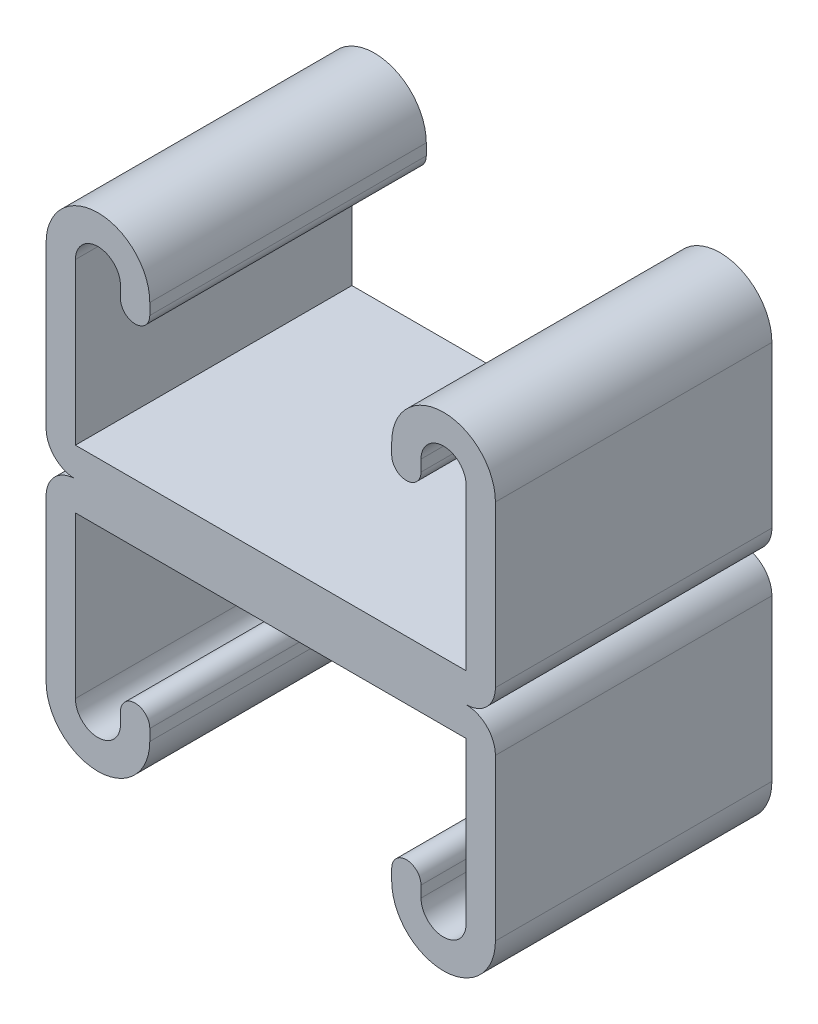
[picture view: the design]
ISO-10303-21;
HEADER;
FILE_DESCRIPTION(('STEP AP214'),'2;1');
FILE_NAME('part.step','',(''),(''),'','','');
FILE_SCHEMA(('AUTOMOTIVE_DESIGN { 1 0 10303 214 1 1 1 1 }'));
ENDSEC;
DATA;
#1=APPLICATION_CONTEXT('core data for automotive mechanical design processes');
#2=APPLICATION_PROTOCOL_DEFINITION('international standard','automotive_design',2000,#1);
#3=PRODUCT_CONTEXT('',#1,'mechanical');
#4=PRODUCT('Part','Part','',(#3));
#5=PRODUCT_RELATED_PRODUCT_CATEGORY('part','',(#4));
#6=PRODUCT_DEFINITION_FORMATION('','',#4);
#7=PRODUCT_DEFINITION_CONTEXT('part definition',#1,'design');
#8=PRODUCT_DEFINITION('design','',#6,#7);
#9=PRODUCT_DEFINITION_SHAPE('','',#8);
#10=(LENGTH_UNIT() NAMED_UNIT(*) SI_UNIT(.MILLI.,.METRE.));
#11=(NAMED_UNIT(*) PLANE_ANGLE_UNIT() SI_UNIT($,.RADIAN.));
#12=(NAMED_UNIT(*) SI_UNIT($,.STERADIAN.) SOLID_ANGLE_UNIT());
#13=UNCERTAINTY_MEASURE_WITH_UNIT(LENGTH_MEASURE(1.E-05),#10,'distance_accuracy_value','');
#14=(GEOMETRIC_REPRESENTATION_CONTEXT(3) GLOBAL_UNCERTAINTY_ASSIGNED_CONTEXT((#13)) GLOBAL_UNIT_ASSIGNED_CONTEXT((#10,
#11,#12)) REPRESENTATION_CONTEXT('',''));
#15=CARTESIAN_POINT('',(0.,0.,0.));
#16=DIRECTION('',(0.,0.,1.));
#17=DIRECTION('',(1.,0.,0.));
#18=AXIS2_PLACEMENT_3D('',#15,#16,#17);
#19=CARTESIAN_POINT('',(-15.875,17.4625,12.7));
#20=DIRECTION('',(0.,0.,-1.));
#21=DIRECTION('',(-1.,0.,0.));
#22=AXIS2_PLACEMENT_3D('',#19,#20,#21);
#23=CYLINDRICAL_SURFACE('',#22,4.7625);
#24=CARTESIAN_POINT('',(-15.875,17.4625,-12.7));
#25=DIRECTION('',(0.,0.,1.));
#26=DIRECTION('',(-1.,0.,0.));
#27=AXIS2_PLACEMENT_3D('',#24,#25,#26);
#28=CIRCLE('',#27,4.7625);
#29=CARTESIAN_POINT('',(-11.1125,17.4625,-12.7));
#30=VERTEX_POINT('',#29);
#31=CARTESIAN_POINT('',(-20.6375,17.4625,-12.7));
#32=VERTEX_POINT('',#31);
#33=EDGE_CURVE('E196',#30,#32,#28,.T.);
#34=ORIENTED_EDGE('',*,*,#33,.T.);
#35=DIRECTION('',(0.,0.,-1.));
#36=VECTOR('',#35,1.);
#37=CARTESIAN_POINT('',(-20.6375,17.4625,12.7));
#38=LINE('',#37,#36);
#39=CARTESIAN_POINT('',(-20.6375,17.4625,12.7));
#40=VERTEX_POINT('',#39);
#41=EDGE_CURVE('E11',#40,#32,#38,.T.);
#42=ORIENTED_EDGE('',*,*,#41,.F.);
#43=CARTESIAN_POINT('',(-15.875,17.4625,12.7));
#44=DIRECTION('',(0.,0.,1.));
#45=DIRECTION('',(-1.,0.,0.));
#46=AXIS2_PLACEMENT_3D('',#43,#44,#45);
#47=CIRCLE('',#46,4.7625);
#48=CARTESIAN_POINT('',(-11.1125,17.4625,12.7));
#49=VERTEX_POINT('',#48);
#50=EDGE_CURVE('E229',#49,#40,#47,.T.);
#51=ORIENTED_EDGE('',*,*,#50,.F.);
#52=DIRECTION('',(0.,0.,-1.));
#53=VECTOR('',#52,1.);
#54=CARTESIAN_POINT('',(-11.1125,17.4625,12.7));
#55=LINE('',#54,#53);
#56=EDGE_CURVE('E192',#49,#30,#55,.T.);
#57=ORIENTED_EDGE('',*,*,#56,.T.);
#58=EDGE_LOOP('',(#34,#42,#51,#57));
#59=FACE_BOUND('',#58,.T.);
#60=ADVANCED_FACE('F39',(#59),#23,.T.);
#61=CARTESIAN_POINT('',(-20.6375,17.4625,12.7));
#62=DIRECTION('',(1.,0.,0.));
#63=DIRECTION('',(0.,1.,0.));
#64=AXIS2_PLACEMENT_3D('',#61,#62,#63);
#65=PLANE('',#64);
#66=DIRECTION('',(0.,-1.,0.));
#67=VECTOR('',#66,1.);
#68=CARTESIAN_POINT('',(-20.6375,17.4625,-12.7));
#69=LINE('',#68,#67);
#70=CARTESIAN_POINT('',(-20.6375,2.6924,-12.7));
#71=VERTEX_POINT('',#70);
#72=EDGE_CURVE('E199',#32,#71,#69,.T.);
#73=ORIENTED_EDGE('',*,*,#72,.T.);
#74=DIRECTION('',(0.,0.,-1.));
#75=VECTOR('',#74,1.);
#76=CARTESIAN_POINT('',(-20.6375,2.6924,12.7));
#77=LINE('',#76,#75);
#78=CARTESIAN_POINT('',(-20.6375,2.6924,12.7));
#79=VERTEX_POINT('',#78);
#80=EDGE_CURVE('E47',#79,#71,#77,.T.);
#81=ORIENTED_EDGE('',*,*,#80,.F.);
#82=DIRECTION('',(0.,-1.,0.));
#83=VECTOR('',#82,1.);
#84=CARTESIAN_POINT('',(-20.6375,17.4625,12.7));
#85=LINE('',#84,#83);
#86=EDGE_CURVE('E126',#40,#79,#85,.T.);
#87=ORIENTED_EDGE('',*,*,#86,.F.);
#88=ORIENTED_EDGE('',*,*,#41,.T.);
#89=EDGE_LOOP('',(#73,#81,#87,#88));
#90=FACE_BOUND('',#89,.T.);
#91=ADVANCED_FACE('F392',(#90),#65,.F.);
#92=CARTESIAN_POINT('',(-17.9451,2.6924,12.7));
#93=DIRECTION('',(0.,0.,-1.));
#94=DIRECTION('',(-1.,0.,0.));
#95=AXIS2_PLACEMENT_3D('',#92,#93,#94);
#96=CYLINDRICAL_SURFACE('',#95,2.6924);
#97=CARTESIAN_POINT('',(-17.9451,2.6924,-12.7));
#98=DIRECTION('',(0.,0.,1.));
#99=DIRECTION('',(-1.,0.,0.));
#100=AXIS2_PLACEMENT_3D('',#97,#98,#99);
#101=CIRCLE('',#100,2.6924);
#102=CARTESIAN_POINT('',(-17.9451,0.,-12.7));
#103=VERTEX_POINT('',#102);
#104=EDGE_CURVE('E202',#71,#103,#101,.T.);
#105=ORIENTED_EDGE('',*,*,#104,.T.);
#106=DIRECTION('',(0.,0.,-1.));
#107=VECTOR('',#106,1.);
#108=CARTESIAN_POINT('',(-17.9451,0.,12.7));
#109=LINE('',#108,#107);
#110=CARTESIAN_POINT('',(-17.9451,0.,12.7));
#111=VERTEX_POINT('',#110);
#112=EDGE_CURVE('E266',#111,#103,#109,.T.);
#113=ORIENTED_EDGE('',*,*,#112,.F.);
#114=CARTESIAN_POINT('',(-17.9451,2.6924,12.7));
#115=DIRECTION('',(0.,0.,1.));
#116=DIRECTION('',(-1.,0.,0.));
#117=AXIS2_PLACEMENT_3D('',#114,#115,#116);
#118=CIRCLE('',#117,2.6924);
#119=EDGE_CURVE('E274',#79,#111,#118,.T.);
#120=ORIENTED_EDGE('',*,*,#119,.F.);
#121=ORIENTED_EDGE('',*,*,#80,.T.);
#122=EDGE_LOOP('',(#105,#113,#120,#121));
#123=FACE_BOUND('',#122,.T.);
#124=ADVANCED_FACE('F272',(#123),#96,.T.);
#125=CARTESIAN_POINT('',(17.9451,2.69240000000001,12.7));
#126=DIRECTION('',(0.,0.,-1.));
#127=DIRECTION('',(-1.,0.,0.));
#128=AXIS2_PLACEMENT_3D('',#125,#126,#127);
#129=CYLINDRICAL_SURFACE('',#128,2.6924);
#130=CARTESIAN_POINT('',(17.9451,2.69240000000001,-12.7));
#131=DIRECTION('',(0.,0.,1.));
#132=DIRECTION('',(1.,0.,0.));
#133=AXIS2_PLACEMENT_3D('',#130,#131,#132);
#134=CIRCLE('',#133,2.6924);
#135=CARTESIAN_POINT('',(17.9451,0.,-12.7));
#136=VERTEX_POINT('',#135);
#137=CARTESIAN_POINT('',(20.6375,2.69240000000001,-12.7));
#138=VERTEX_POINT('',#137);
#139=EDGE_CURVE('E204',#136,#138,#134,.T.);
#140=ORIENTED_EDGE('',*,*,#139,.T.);
#141=DIRECTION('',(0.,0.,-1.));
#142=VECTOR('',#141,1.);
#143=CARTESIAN_POINT('',(20.6375,2.69240000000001,12.7));
#144=LINE('',#143,#142);
#145=CARTESIAN_POINT('',(20.6375,2.69240000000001,12.7));
#146=VERTEX_POINT('',#145);
#147=EDGE_CURVE('E260',#146,#138,#144,.T.);
#148=ORIENTED_EDGE('',*,*,#147,.F.);
#149=CARTESIAN_POINT('',(17.9451,2.69240000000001,12.7));
#150=DIRECTION('',(0.,0.,1.));
#151=DIRECTION('',(1.,0.,0.));
#152=AXIS2_PLACEMENT_3D('',#149,#150,#151);
#153=CIRCLE('',#152,2.6924);
#154=CARTESIAN_POINT('',(17.9451,0.,12.7));
#155=VERTEX_POINT('',#154);
#156=EDGE_CURVE('E348',#155,#146,#153,.T.);
#157=ORIENTED_EDGE('',*,*,#156,.F.);
#158=DIRECTION('',(0.,0.,-1.));
#159=VECTOR('',#158,1.);
#160=CARTESIAN_POINT('',(17.9451,0.,12.7));
#161=LINE('',#160,#159);
#162=EDGE_CURVE('E263',#155,#136,#161,.T.);
#163=ORIENTED_EDGE('',*,*,#162,.T.);
#164=EDGE_LOOP('',(#140,#148,#157,#163));
#165=FACE_BOUND('',#164,.T.);
#166=ADVANCED_FACE('F399',(#165),#129,.T.);
#167=CARTESIAN_POINT('',(20.6375,2.69240000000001,12.7));
#168=DIRECTION('',(-1.,0.,0.));
#169=DIRECTION('',(0.,-1.,0.));
#170=AXIS2_PLACEMENT_3D('',#167,#168,#169);
#171=PLANE('',#170);
#172=DIRECTION('',(0.,1.,0.));
#173=VECTOR('',#172,1.);
#174=CARTESIAN_POINT('',(20.6375,2.69240000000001,-12.7));
#175=LINE('',#174,#173);
#176=CARTESIAN_POINT('',(20.6375,17.4625,-12.7));
#177=VERTEX_POINT('',#176);
#178=EDGE_CURVE('E206',#138,#177,#175,.T.);
#179=ORIENTED_EDGE('',*,*,#178,.T.);
#180=DIRECTION('',(0.,0.,-1.));
#181=VECTOR('',#180,1.);
#182=CARTESIAN_POINT('',(20.6375,17.4625,12.7));
#183=LINE('',#182,#181);
#184=CARTESIAN_POINT('',(20.6375,17.4625,12.7));
#185=VERTEX_POINT('',#184);
#186=EDGE_CURVE('E257',#185,#177,#183,.T.);
#187=ORIENTED_EDGE('',*,*,#186,.F.);
#188=DIRECTION('',(0.,1.,0.));
#189=VECTOR('',#188,1.);
#190=CARTESIAN_POINT('',(20.6375,2.69240000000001,12.7));
#191=LINE('',#190,#189);
#192=EDGE_CURVE('E350',#146,#185,#191,.T.);
#193=ORIENTED_EDGE('',*,*,#192,.F.);
#194=ORIENTED_EDGE('',*,*,#147,.T.);
#195=EDGE_LOOP('',(#179,#187,#193,#194));
#196=FACE_BOUND('',#195,.T.);
#197=ADVANCED_FACE('F404',(#196),#171,.F.);
#198=CARTESIAN_POINT('',(15.875,17.4625,12.7));
#199=DIRECTION('',(0.,0.,-1.));
#200=DIRECTION('',(-1.,0.,0.));
#201=AXIS2_PLACEMENT_3D('',#198,#199,#200);
#202=CYLINDRICAL_SURFACE('',#201,4.7625);
#203=CARTESIAN_POINT('',(15.875,17.4625,-12.7));
#204=DIRECTION('',(0.,0.,1.));
#205=DIRECTION('',(1.,0.,0.));
#206=AXIS2_PLACEMENT_3D('',#203,#204,#205);
#207=CIRCLE('',#206,4.7625);
#208=CARTESIAN_POINT('',(11.1125,17.4625,-12.7));
#209=VERTEX_POINT('',#208);
#210=EDGE_CURVE('E208',#177,#209,#207,.T.);
#211=ORIENTED_EDGE('',*,*,#210,.T.);
#212=DIRECTION('',(0.,0.,-1.));
#213=VECTOR('',#212,1.);
#214=CARTESIAN_POINT('',(11.1125,17.4625,12.7));
#215=LINE('',#214,#213);
#216=CARTESIAN_POINT('',(11.1125,17.4625,12.7));
#217=VERTEX_POINT('',#216);
#218=EDGE_CURVE('E254',#217,#209,#215,.T.);
#219=ORIENTED_EDGE('',*,*,#218,.F.);
#220=CARTESIAN_POINT('',(15.875,17.4625,12.7));
#221=DIRECTION('',(0.,0.,1.));
#222=DIRECTION('',(1.,0.,0.));
#223=AXIS2_PLACEMENT_3D('',#220,#221,#222);
#224=CIRCLE('',#223,4.7625);
#225=EDGE_CURVE('E352',#185,#217,#224,.T.);
#226=ORIENTED_EDGE('',*,*,#225,.F.);
#227=ORIENTED_EDGE('',*,*,#186,.T.);
#228=EDGE_LOOP('',(#211,#219,#226,#227));
#229=FACE_BOUND('',#228,.T.);
#230=ADVANCED_FACE('F407',(#229),#202,.T.);
#231=CARTESIAN_POINT('',(11.1125,17.4625,12.7));
#232=DIRECTION('',(1.,0.,0.));
#233=DIRECTION('',(0.,0.,-1.));
#234=AXIS2_PLACEMENT_3D('',#231,#232,#233);
#235=PLANE('',#234);
#236=DIRECTION('',(0.,-1.,0.));
#237=VECTOR('',#236,1.);
#238=CARTESIAN_POINT('',(11.1125,17.4625,-12.7));
#239=LINE('',#238,#237);
#240=CARTESIAN_POINT('',(11.1125,16.42745,-12.7));
#241=VERTEX_POINT('',#240);
#242=EDGE_CURVE('E210',#209,#241,#239,.T.);
#243=ORIENTED_EDGE('',*,*,#242,.T.);
#244=DIRECTION('',(0.,0.,-1.));
#245=VECTOR('',#244,1.);
#246=CARTESIAN_POINT('',(11.1125,16.42745,12.7));
#247=LINE('',#246,#245);
#248=CARTESIAN_POINT('',(11.1125,16.42745,12.7));
#249=VERTEX_POINT('',#248);
#250=EDGE_CURVE('E251',#249,#241,#247,.T.);
#251=ORIENTED_EDGE('',*,*,#250,.F.);
#252=DIRECTION('',(0.,-1.,0.));
#253=VECTOR('',#252,1.);
#254=CARTESIAN_POINT('',(11.1125,17.4625,12.7));
#255=LINE('',#254,#253);
#256=EDGE_CURVE('E354',#217,#249,#255,.T.);
#257=ORIENTED_EDGE('',*,*,#256,.F.);
#258=ORIENTED_EDGE('',*,*,#218,.T.);
#259=EDGE_LOOP('',(#243,#251,#257,#258));
#260=FACE_BOUND('',#259,.T.);
#261=ADVANCED_FACE('F411',(#260),#235,.F.);
#262=CARTESIAN_POINT('',(12.4587,16.42745,12.7));
#263=DIRECTION('',(0.,0.,-1.));
#264=DIRECTION('',(-1.,0.,0.));
#265=AXIS2_PLACEMENT_3D('',#262,#263,#264);
#266=CYLINDRICAL_SURFACE('',#265,1.3462);
#267=CARTESIAN_POINT('',(12.4587,16.42745,-12.7));
#268=DIRECTION('',(0.,0.,1.));
#269=DIRECTION('',(1.,0.,0.));
#270=AXIS2_PLACEMENT_3D('',#267,#268,#269);
#271=CIRCLE('',#270,1.3462);
#272=CARTESIAN_POINT('',(13.8049,16.42745,-12.7));
#273=VERTEX_POINT('',#272);
#274=EDGE_CURVE('E212',#241,#273,#271,.T.);
#275=ORIENTED_EDGE('',*,*,#274,.T.);
#276=DIRECTION('',(0.,0.,-1.));
#277=VECTOR('',#276,1.);
#278=CARTESIAN_POINT('',(13.8049,16.42745,12.7));
#279=LINE('',#278,#277);
#280=CARTESIAN_POINT('',(13.8049,16.42745,12.7));
#281=VERTEX_POINT('',#280);
#282=EDGE_CURVE('E248',#281,#273,#279,.T.);
#283=ORIENTED_EDGE('',*,*,#282,.F.);
#284=CARTESIAN_POINT('',(12.4587,16.42745,12.7));
#285=DIRECTION('',(0.,0.,1.));
#286=DIRECTION('',(1.,0.,0.));
#287=AXIS2_PLACEMENT_3D('',#284,#285,#286);
#288=CIRCLE('',#287,1.3462);
#289=EDGE_CURVE('E356',#249,#281,#288,.T.);
#290=ORIENTED_EDGE('',*,*,#289,.F.);
#291=ORIENTED_EDGE('',*,*,#250,.T.);
#292=EDGE_LOOP('',(#275,#283,#290,#291));
#293=FACE_BOUND('',#292,.T.);
#294=ADVANCED_FACE('F415',(#293),#266,.T.);
#295=CARTESIAN_POINT('',(13.8049,17.4625,12.7));
#296=DIRECTION('',(-1.,0.,0.));
#297=DIRECTION('',(0.,-1.,0.));
#298=AXIS2_PLACEMENT_3D('',#295,#296,#297);
#299=PLANE('',#298);
#300=DIRECTION('',(0.,1.,0.));
#301=VECTOR('',#300,1.);
#302=CARTESIAN_POINT('',(13.8049,17.4625,-12.7));
#303=LINE('',#302,#301);
#304=CARTESIAN_POINT('',(13.8049,17.4625,-12.7));
#305=VERTEX_POINT('',#304);
#306=EDGE_CURVE('E214',#273,#305,#303,.T.);
#307=ORIENTED_EDGE('',*,*,#306,.T.);
#308=DIRECTION('',(0.,0.,-1.));
#309=VECTOR('',#308,1.);
#310=CARTESIAN_POINT('',(13.8049,17.4625,12.7));
#311=LINE('',#310,#309);
#312=CARTESIAN_POINT('',(13.8049,17.4625,12.7));
#313=VERTEX_POINT('',#312);
#314=EDGE_CURVE('E245',#313,#305,#311,.T.);
#315=ORIENTED_EDGE('',*,*,#314,.F.);
#316=DIRECTION('',(0.,1.,0.));
#317=VECTOR('',#316,1.);
#318=CARTESIAN_POINT('',(13.8049,17.4625,12.7));
#319=LINE('',#318,#317);
#320=EDGE_CURVE('E358',#281,#313,#319,.T.);
#321=ORIENTED_EDGE('',*,*,#320,.F.);
#322=ORIENTED_EDGE('',*,*,#282,.T.);
#323=EDGE_LOOP('',(#307,#315,#321,#322));
#324=FACE_BOUND('',#323,.T.);
#325=ADVANCED_FACE('F419',(#324),#299,.F.);
#326=CARTESIAN_POINT('',(15.875,17.4625,12.7));
#327=DIRECTION('',(0.,0.,-1.));
#328=DIRECTION('',(-1.,0.,0.));
#329=AXIS2_PLACEMENT_3D('',#326,#327,#328);
#330=CYLINDRICAL_SURFACE('',#329,2.07010000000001);
#331=CARTESIAN_POINT('',(15.875,17.4625,-12.7));
#332=DIRECTION('',(0.,0.,-1.));
#333=DIRECTION('',(1.,0.,0.));
#334=AXIS2_PLACEMENT_3D('',#331,#332,#333);
#335=CIRCLE('',#334,2.07010000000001);
#336=CARTESIAN_POINT('',(17.9451,17.4625,-12.7));
#337=VERTEX_POINT('',#336);
#338=EDGE_CURVE('E216',#305,#337,#335,.T.);
#339=ORIENTED_EDGE('',*,*,#338,.T.);
#340=DIRECTION('',(0.,0.,-1.));
#341=VECTOR('',#340,1.);
#342=CARTESIAN_POINT('',(17.9451,17.4625,12.7));
#343=LINE('',#342,#341);
#344=CARTESIAN_POINT('',(17.9451,17.4625,12.7));
#345=VERTEX_POINT('',#344);
#346=EDGE_CURVE('E242',#345,#337,#343,.T.);
#347=ORIENTED_EDGE('',*,*,#346,.F.);
#348=CARTESIAN_POINT('',(15.875,17.4625,12.7));
#349=DIRECTION('',(0.,0.,-1.));
#350=DIRECTION('',(1.,0.,0.));
#351=AXIS2_PLACEMENT_3D('',#348,#349,#350);
#352=CIRCLE('',#351,2.07010000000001);
#353=EDGE_CURVE('E360',#313,#345,#352,.T.);
#354=ORIENTED_EDGE('',*,*,#353,.F.);
#355=ORIENTED_EDGE('',*,*,#314,.T.);
#356=EDGE_LOOP('',(#339,#347,#354,#355));
#357=FACE_BOUND('',#356,.T.);
#358=ADVANCED_FACE('F423',(#357),#330,.F.);
#359=CARTESIAN_POINT('',(17.9451,2.6924,12.7));
#360=DIRECTION('',(1.,0.,0.));
#361=DIRECTION('',(0.,0.,-1.));
#362=AXIS2_PLACEMENT_3D('',#359,#360,#361);
#363=PLANE('',#362);
#364=DIRECTION('',(0.,-1.,0.));
#365=VECTOR('',#364,1.);
#366=CARTESIAN_POINT('',(17.9451,2.6924,-12.7));
#367=LINE('',#366,#365);
#368=CARTESIAN_POINT('',(17.9451,2.6924,-12.7));
#369=VERTEX_POINT('',#368);
#370=EDGE_CURVE('E218',#337,#369,#367,.T.);
#371=ORIENTED_EDGE('',*,*,#370,.T.);
#372=DIRECTION('',(0.,0.,-1.));
#373=VECTOR('',#372,1.);
#374=CARTESIAN_POINT('',(17.9451,2.6924,12.7));
#375=LINE('',#374,#373);
#376=CARTESIAN_POINT('',(17.9451,2.6924,12.7));
#377=VERTEX_POINT('',#376);
#378=EDGE_CURVE('E239',#377,#369,#375,.T.);
#379=ORIENTED_EDGE('',*,*,#378,.F.);
#380=DIRECTION('',(0.,-1.,0.));
#381=VECTOR('',#380,1.);
#382=CARTESIAN_POINT('',(17.9451,2.6924,12.7));
#383=LINE('',#382,#381);
#384=EDGE_CURVE('E362',#345,#377,#383,.T.);
#385=ORIENTED_EDGE('',*,*,#384,.F.);
#386=ORIENTED_EDGE('',*,*,#346,.T.);
#387=EDGE_LOOP('',(#371,#379,#385,#386));
#388=FACE_BOUND('',#387,.T.);
#389=ADVANCED_FACE('F427',(#388),#363,.F.);
#390=CARTESIAN_POINT('',(-17.9451,2.6924,12.7));
#391=DIRECTION('',(0.,-1.,0.));
#392=DIRECTION('',(0.,0.,-1.));
#393=AXIS2_PLACEMENT_3D('',#390,#391,#392);
#394=PLANE('',#393);
#395=DIRECTION('',(-1.,0.,0.));
#396=VECTOR('',#395,1.);
#397=CARTESIAN_POINT('',(-17.9451,2.6924,-12.7));
#398=LINE('',#397,#396);
#399=CARTESIAN_POINT('',(-17.9451,2.6924,-12.7));
#400=VERTEX_POINT('',#399);
#401=EDGE_CURVE('E220',#369,#400,#398,.T.);
#402=ORIENTED_EDGE('',*,*,#401,.T.);
#403=DIRECTION('',(0.,0.,-1.));
#404=VECTOR('',#403,1.);
#405=CARTESIAN_POINT('',(-17.9451,2.6924,12.7));
#406=LINE('',#405,#404);
#407=CARTESIAN_POINT('',(-17.9451,2.6924,12.7));
#408=VERTEX_POINT('',#407);
#409=EDGE_CURVE('E236',#408,#400,#406,.T.);
#410=ORIENTED_EDGE('',*,*,#409,.F.);
#411=DIRECTION('',(-1.,0.,0.));
#412=VECTOR('',#411,1.);
#413=CARTESIAN_POINT('',(-17.9451,2.6924,12.7));
#414=LINE('',#413,#412);
#415=EDGE_CURVE('E364',#377,#408,#414,.T.);
#416=ORIENTED_EDGE('',*,*,#415,.F.);
#417=ORIENTED_EDGE('',*,*,#378,.T.);
#418=EDGE_LOOP('',(#402,#410,#416,#417));
#419=FACE_BOUND('',#418,.T.);
#420=ADVANCED_FACE('F431',(#419),#394,.F.);
#421=CARTESIAN_POINT('',(-17.9451,17.4625,12.7));
#422=DIRECTION('',(-1.,0.,0.));
#423=DIRECTION('',(0.,-1.,0.));
#424=AXIS2_PLACEMENT_3D('',#421,#422,#423);
#425=PLANE('',#424);
#426=DIRECTION('',(0.,1.,0.));
#427=VECTOR('',#426,1.);
#428=CARTESIAN_POINT('',(-17.9451,17.4625,-12.7));
#429=LINE('',#428,#427);
#430=CARTESIAN_POINT('',(-17.9451,17.4625,-12.7));
#431=VERTEX_POINT('',#430);
#432=EDGE_CURVE('E222',#400,#431,#429,.T.);
#433=ORIENTED_EDGE('',*,*,#432,.T.);
#434=DIRECTION('',(0.,0.,-1.));
#435=VECTOR('',#434,1.);
#436=CARTESIAN_POINT('',(-17.9451,17.4625,12.7));
#437=LINE('',#436,#435);
#438=CARTESIAN_POINT('',(-17.9451,17.4625,12.7));
#439=VERTEX_POINT('',#438);
#440=EDGE_CURVE('E233',#439,#431,#437,.T.);
#441=ORIENTED_EDGE('',*,*,#440,.F.);
#442=DIRECTION('',(0.,1.,0.));
#443=VECTOR('',#442,1.);
#444=CARTESIAN_POINT('',(-17.9451,17.4625,12.7));
#445=LINE('',#444,#443);
#446=EDGE_CURVE('E366',#408,#439,#445,.T.);
#447=ORIENTED_EDGE('',*,*,#446,.F.);
#448=ORIENTED_EDGE('',*,*,#409,.T.);
#449=EDGE_LOOP('',(#433,#441,#447,#448));
#450=FACE_BOUND('',#449,.T.);
#451=ADVANCED_FACE('F372',(#450),#425,.F.);
#452=CARTESIAN_POINT('',(-15.875,17.4625,12.7));
#453=DIRECTION('',(0.,0.,-1.));
#454=DIRECTION('',(-1.,0.,0.));
#455=AXIS2_PLACEMENT_3D('',#452,#453,#454);
#456=CYLINDRICAL_SURFACE('',#455,2.0701);
#457=CARTESIAN_POINT('',(-15.875,17.4625,-12.7));
#458=DIRECTION('',(0.,0.,-1.));
#459=DIRECTION('',(-1.,0.,0.));
#460=AXIS2_PLACEMENT_3D('',#457,#458,#459);
#461=CIRCLE('',#460,2.0701);
#462=CARTESIAN_POINT('',(-13.8049,17.4625,-12.7));
#463=VERTEX_POINT('',#462);
#464=EDGE_CURVE('E224',#431,#463,#461,.T.);
#465=ORIENTED_EDGE('',*,*,#464,.T.);
#466=DIRECTION('',(0.,0.,-1.));
#467=VECTOR('',#466,1.);
#468=CARTESIAN_POINT('',(-13.8049,17.4625,12.7));
#469=LINE('',#468,#467);
#470=CARTESIAN_POINT('',(-13.8049,17.4625,12.7));
#471=VERTEX_POINT('',#470);
#472=EDGE_CURVE('E187',#471,#463,#469,.T.);
#473=ORIENTED_EDGE('',*,*,#472,.F.);
#474=CARTESIAN_POINT('',(-15.875,17.4625,12.7));
#475=DIRECTION('',(0.,0.,-1.));
#476=DIRECTION('',(-1.,0.,0.));
#477=AXIS2_PLACEMENT_3D('',#474,#475,#476);
#478=CIRCLE('',#477,2.0701);
#479=EDGE_CURVE('E178',#439,#471,#478,.T.);
#480=ORIENTED_EDGE('',*,*,#479,.F.);
#481=ORIENTED_EDGE('',*,*,#440,.T.);
#482=EDGE_LOOP('',(#465,#473,#480,#481));
#483=FACE_BOUND('',#482,.T.);
#484=ADVANCED_FACE('F376',(#483),#456,.F.);
#485=CARTESIAN_POINT('',(-13.8049,17.4625,12.7));
#486=DIRECTION('',(1.,0.,0.));
#487=DIRECTION('',(0.,1.,0.));
#488=AXIS2_PLACEMENT_3D('',#485,#486,#487);
#489=PLANE('',#488);
#490=DIRECTION('',(0.,-1.,0.));
#491=VECTOR('',#490,1.);
#492=CARTESIAN_POINT('',(-13.8049,17.4625,-12.7));
#493=LINE('',#492,#491);
#494=CARTESIAN_POINT('',(-13.8049,16.42745,-12.7));
#495=VERTEX_POINT('',#494);
#496=EDGE_CURVE('E186',#463,#495,#493,.T.);
#497=ORIENTED_EDGE('',*,*,#496,.T.);
#498=DIRECTION('',(0.,0.,-1.));
#499=VECTOR('',#498,1.);
#500=CARTESIAN_POINT('',(-13.8049,16.42745,12.7));
#501=LINE('',#500,#499);
#502=CARTESIAN_POINT('',(-13.8049,16.42745,12.7));
#503=VERTEX_POINT('',#502);
#504=EDGE_CURVE('E183',#503,#495,#501,.T.);
#505=ORIENTED_EDGE('',*,*,#504,.F.);
#506=DIRECTION('',(0.,-1.,0.));
#507=VECTOR('',#506,1.);
#508=CARTESIAN_POINT('',(-13.8049,17.4625,12.7));
#509=LINE('',#508,#507);
#510=EDGE_CURVE('E172',#471,#503,#509,.T.);
#511=ORIENTED_EDGE('',*,*,#510,.F.);
#512=ORIENTED_EDGE('',*,*,#472,.T.);
#513=EDGE_LOOP('',(#497,#505,#511,#512));
#514=FACE_BOUND('',#513,.T.);
#515=ADVANCED_FACE('F184',(#514),#489,.F.);
#516=CARTESIAN_POINT('',(-12.4587,16.42745,12.7));
#517=DIRECTION('',(0.,0.,-1.));
#518=DIRECTION('',(-1.,0.,0.));
#519=AXIS2_PLACEMENT_3D('',#516,#517,#518);
#520=CYLINDRICAL_SURFACE('',#519,1.3462);
#521=CARTESIAN_POINT('',(-12.4587,16.42745,-12.7));
#522=DIRECTION('',(0.,0.,1.));
#523=DIRECTION('',(-1.,0.,0.));
#524=AXIS2_PLACEMENT_3D('',#521,#522,#523);
#525=CIRCLE('',#524,1.3462);
#526=CARTESIAN_POINT('',(-11.1125,16.42745,-12.7));
#527=VERTEX_POINT('',#526);
#528=EDGE_CURVE('E112',#495,#527,#525,.T.);
#529=ORIENTED_EDGE('',*,*,#528,.T.);
#530=DIRECTION('',(0.,0.,-1.));
#531=VECTOR('',#530,1.);
#532=CARTESIAN_POINT('',(-11.1125,16.42745,12.7));
#533=LINE('',#532,#531);
#534=CARTESIAN_POINT('',(-11.1125,16.42745,12.7));
#535=VERTEX_POINT('',#534);
#536=EDGE_CURVE('E188',#535,#527,#533,.T.);
#537=ORIENTED_EDGE('',*,*,#536,.F.);
#538=CARTESIAN_POINT('',(-12.4587,16.42745,12.7));
#539=DIRECTION('',(0.,0.,1.));
#540=DIRECTION('',(-1.,0.,0.));
#541=AXIS2_PLACEMENT_3D('',#538,#539,#540);
#542=CIRCLE('',#541,1.3462);
#543=EDGE_CURVE('E176',#503,#535,#542,.T.);
#544=ORIENTED_EDGE('',*,*,#543,.F.);
#545=ORIENTED_EDGE('',*,*,#504,.T.);
#546=EDGE_LOOP('',(#529,#537,#544,#545));
#547=FACE_BOUND('',#546,.T.);
#548=ADVANCED_FACE('F190',(#547),#520,.T.);
#549=CARTESIAN_POINT('',(-11.1125,17.4625,12.7));
#550=DIRECTION('',(-1.,0.,0.));
#551=DIRECTION('',(0.,0.,1.));
#552=AXIS2_PLACEMENT_3D('',#549,#550,#551);
#553=PLANE('',#552);
#554=DIRECTION('',(0.,1.,0.));
#555=VECTOR('',#554,1.);
#556=CARTESIAN_POINT('',(-11.1125,17.4625,-12.7));
#557=LINE('',#556,#555);
#558=EDGE_CURVE('E118',#527,#30,#557,.T.);
#559=ORIENTED_EDGE('',*,*,#558,.T.);
#560=ORIENTED_EDGE('',*,*,#56,.F.);
#561=DIRECTION('',(0.,1.,0.));
#562=VECTOR('',#561,1.);
#563=CARTESIAN_POINT('',(-11.1125,17.4625,12.7));
#564=LINE('',#563,#562);
#565=EDGE_CURVE('E55',#535,#49,#564,.T.);
#566=ORIENTED_EDGE('',*,*,#565,.F.);
#567=ORIENTED_EDGE('',*,*,#536,.T.);
#568=EDGE_LOOP('',(#559,#560,#566,#567));
#569=FACE_BOUND('',#568,.T.);
#570=ADVANCED_FACE('F380',(#569),#553,.F.);
#571=CARTESIAN_POINT('',(-15.875,17.4625,12.7));
#572=DIRECTION('',(0.,0.,-1.));
#573=DIRECTION('',(-1.,0.,0.));
#574=AXIS2_PLACEMENT_3D('',#571,#572,#573);
#575=PLANE('',#574);
#576=ORIENTED_EDGE('',*,*,#50,.T.);
#577=ORIENTED_EDGE('',*,*,#86,.T.);
#578=ORIENTED_EDGE('',*,*,#119,.T.);
#579=CARTESIAN_POINT('',(-17.9451,-2.6924,12.7));
#580=DIRECTION('',(0.,0.,-1.));
#581=DIRECTION('',(-1.,0.,0.));
#582=AXIS2_PLACEMENT_3D('',#579,#580,#581);
#583=CIRCLE('',#582,2.6924);
#584=CARTESIAN_POINT('',(-20.6375,-2.6924,12.7));
#585=VERTEX_POINT('',#584);
#586=EDGE_CURVE('E779',#585,#111,#583,.T.);
#587=ORIENTED_EDGE('',*,*,#586,.F.);
#588=DIRECTION('',(0.,1.,0.));
#589=VECTOR('',#588,1.);
#590=CARTESIAN_POINT('',(-20.6375,-17.4625,12.7));
#591=LINE('',#590,#589);
#592=CARTESIAN_POINT('',(-20.6375,-17.4625,12.7));
#593=VERTEX_POINT('',#592);
#594=EDGE_CURVE('E301',#593,#585,#591,.T.);
#595=ORIENTED_EDGE('',*,*,#594,.F.);
#596=CARTESIAN_POINT('',(-15.875,-17.4625,12.7));
#597=DIRECTION('',(0.,0.,-1.));
#598=DIRECTION('',(-1.,0.,0.));
#599=AXIS2_PLACEMENT_3D('',#596,#597,#598);
#600=CIRCLE('',#599,4.7625);
#601=CARTESIAN_POINT('',(-11.1125,-17.4625,12.7));
#602=VERTEX_POINT('',#601);
#603=EDGE_CURVE('E290',#602,#593,#600,.T.);
#604=ORIENTED_EDGE('',*,*,#603,.F.);
#605=DIRECTION('',(0.,-1.,0.));
#606=VECTOR('',#605,1.);
#607=CARTESIAN_POINT('',(-11.1125,-17.4625,12.7));
#608=LINE('',#607,#606);
#609=CARTESIAN_POINT('',(-11.1125,-16.42745,12.7));
#610=VERTEX_POINT('',#609);
#611=EDGE_CURVE('E728',#610,#602,#608,.T.);
#612=ORIENTED_EDGE('',*,*,#611,.F.);
#613=CARTESIAN_POINT('',(-12.4587,-16.42745,12.7));
#614=DIRECTION('',(0.,0.,-1.));
#615=DIRECTION('',(-1.,0.,0.));
#616=AXIS2_PLACEMENT_3D('',#613,#614,#615);
#617=CIRCLE('',#616,1.3462);
#618=CARTESIAN_POINT('',(-13.8049,-16.42745,12.7));
#619=VERTEX_POINT('',#618);
#620=EDGE_CURVE('E737',#619,#610,#617,.T.);
#621=ORIENTED_EDGE('',*,*,#620,.F.);
#622=DIRECTION('',(0.,1.,0.));
#623=VECTOR('',#622,1.);
#624=CARTESIAN_POINT('',(-13.8049,-17.4625,12.7));
#625=LINE('',#624,#623);
#626=CARTESIAN_POINT('',(-13.8049,-17.4625,12.7));
#627=VERTEX_POINT('',#626);
#628=EDGE_CURVE('E741',#627,#619,#625,.T.);
#629=ORIENTED_EDGE('',*,*,#628,.F.);
#630=CARTESIAN_POINT('',(-15.875,-17.4625,12.7));
#631=DIRECTION('',(0.,0.,1.));
#632=DIRECTION('',(-1.,0.,0.));
#633=AXIS2_PLACEMENT_3D('',#630,#631,#632);
#634=CIRCLE('',#633,2.0701);
#635=CARTESIAN_POINT('',(-17.9451,-17.4625,12.7));
#636=VERTEX_POINT('',#635);
#637=EDGE_CURVE('E743',#636,#627,#634,.T.);
#638=ORIENTED_EDGE('',*,*,#637,.F.);
#639=DIRECTION('',(0.,-1.,0.));
#640=VECTOR('',#639,1.);
#641=CARTESIAN_POINT('',(-17.9451,-17.4625,12.7));
#642=LINE('',#641,#640);
#643=CARTESIAN_POINT('',(-17.9451,-2.6924,12.7));
#644=VERTEX_POINT('',#643);
#645=EDGE_CURVE('E749',#644,#636,#642,.T.);
#646=ORIENTED_EDGE('',*,*,#645,.F.);
#647=DIRECTION('',(-1.,0.,0.));
#648=VECTOR('',#647,1.);
#649=CARTESIAN_POINT('',(-17.9451,-2.6924,12.7));
#650=LINE('',#649,#648);
#651=CARTESIAN_POINT('',(17.9451,-2.6924,12.7));
#652=VERTEX_POINT('',#651);
#653=EDGE_CURVE('E752',#652,#644,#650,.T.);
#654=ORIENTED_EDGE('',*,*,#653,.F.);
#655=DIRECTION('',(0.,1.,0.));
#656=VECTOR('',#655,1.);
#657=CARTESIAN_POINT('',(17.9451,-2.6924,12.7));
#658=LINE('',#657,#656);
#659=CARTESIAN_POINT('',(17.9451,-17.4625,12.7));
#660=VERTEX_POINT('',#659);
#661=EDGE_CURVE('E755',#660,#652,#658,.T.);
#662=ORIENTED_EDGE('',*,*,#661,.F.);
#663=CARTESIAN_POINT('',(15.875,-17.4625,12.7));
#664=DIRECTION('',(0.,0.,1.));
#665=DIRECTION('',(1.,0.,0.));
#666=AXIS2_PLACEMENT_3D('',#663,#664,#665);
#667=CIRCLE('',#666,2.07010000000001);
#668=CARTESIAN_POINT('',(13.8049,-17.4625,12.7));
#669=VERTEX_POINT('',#668);
#670=EDGE_CURVE('E758',#669,#660,#667,.T.);
#671=ORIENTED_EDGE('',*,*,#670,.F.);
#672=DIRECTION('',(0.,-1.,0.));
#673=VECTOR('',#672,1.);
#674=CARTESIAN_POINT('',(13.8049,-17.4625,12.7));
#675=LINE('',#674,#673);
#676=CARTESIAN_POINT('',(13.8049,-16.42745,12.7));
#677=VERTEX_POINT('',#676);
#678=EDGE_CURVE('E761',#677,#669,#675,.T.);
#679=ORIENTED_EDGE('',*,*,#678,.F.);
#680=CARTESIAN_POINT('',(12.4587,-16.42745,12.7));
#681=DIRECTION('',(0.,0.,-1.));
#682=DIRECTION('',(1.,0.,0.));
#683=AXIS2_PLACEMENT_3D('',#680,#681,#682);
#684=CIRCLE('',#683,1.3462);
#685=CARTESIAN_POINT('',(11.1125,-16.42745,12.7));
#686=VERTEX_POINT('',#685);
#687=EDGE_CURVE('E764',#686,#677,#684,.T.);
#688=ORIENTED_EDGE('',*,*,#687,.F.);
#689=DIRECTION('',(0.,1.,0.));
#690=VECTOR('',#689,1.);
#691=CARTESIAN_POINT('',(11.1125,-17.4625,12.7));
#692=LINE('',#691,#690);
#693=CARTESIAN_POINT('',(11.1125,-17.4625,12.7));
#694=VERTEX_POINT('',#693);
#695=EDGE_CURVE('E767',#694,#686,#692,.T.);
#696=ORIENTED_EDGE('',*,*,#695,.F.);
#697=CARTESIAN_POINT('',(15.875,-17.4625,12.7));
#698=DIRECTION('',(0.,0.,-1.));
#699=DIRECTION('',(1.,0.,0.));
#700=AXIS2_PLACEMENT_3D('',#697,#698,#699);
#701=CIRCLE('',#700,4.7625);
#702=CARTESIAN_POINT('',(20.6375,-17.4625,12.7));
#703=VERTEX_POINT('',#702);
#704=EDGE_CURVE('E770',#703,#694,#701,.T.);
#705=ORIENTED_EDGE('',*,*,#704,.F.);
#706=DIRECTION('',(0.,-1.,0.));
#707=VECTOR('',#706,1.);
#708=CARTESIAN_POINT('',(20.6375,-2.69240000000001,12.7));
#709=LINE('',#708,#707);
#710=CARTESIAN_POINT('',(20.6375,-2.69240000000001,12.7));
#711=VERTEX_POINT('',#710);
#712=EDGE_CURVE('E773',#711,#703,#709,.T.);
#713=ORIENTED_EDGE('',*,*,#712,.F.);
#714=CARTESIAN_POINT('',(17.9451,-2.69240000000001,12.7));
#715=DIRECTION('',(0.,0.,-1.));
#716=DIRECTION('',(1.,0.,0.));
#717=AXIS2_PLACEMENT_3D('',#714,#715,#716);
#718=CIRCLE('',#717,2.6924);
#719=EDGE_CURVE('E776',#155,#711,#718,.T.);
#720=ORIENTED_EDGE('',*,*,#719,.F.);
#721=ORIENTED_EDGE('',*,*,#156,.T.);
#722=ORIENTED_EDGE('',*,*,#192,.T.);
#723=ORIENTED_EDGE('',*,*,#225,.T.);
#724=ORIENTED_EDGE('',*,*,#256,.T.);
#725=ORIENTED_EDGE('',*,*,#289,.T.);
#726=ORIENTED_EDGE('',*,*,#320,.T.);
#727=ORIENTED_EDGE('',*,*,#353,.T.);
#728=ORIENTED_EDGE('',*,*,#384,.T.);
#729=ORIENTED_EDGE('',*,*,#415,.T.);
#730=ORIENTED_EDGE('',*,*,#446,.T.);
#731=ORIENTED_EDGE('',*,*,#479,.T.);
#732=ORIENTED_EDGE('',*,*,#510,.T.);
#733=ORIENTED_EDGE('',*,*,#543,.T.);
#734=ORIENTED_EDGE('',*,*,#565,.T.);
#735=EDGE_LOOP('',(#576,#577,#578,#587,#595,#604,#612,#621,#629,#638,#646,#654,#662,#671,#679,
#688,#696,#705,#713,#720,#721,#722,#723,#724,#725,#726,#727,#728,#729,#730,#731,#732,#733,#734));
#736=FACE_BOUND('',#735,.T.);
#737=ADVANCED_FACE('F174',(#736),#575,.F.);
#738=CARTESIAN_POINT('',(-15.875,17.4625,-12.7));
#739=DIRECTION('',(0.,0.,-1.));
#740=DIRECTION('',(-1.,0.,0.));
#741=AXIS2_PLACEMENT_3D('',#738,#739,#740);
#742=PLANE('',#741);
#743=ORIENTED_EDGE('',*,*,#33,.F.);
#744=ORIENTED_EDGE('',*,*,#558,.F.);
#745=ORIENTED_EDGE('',*,*,#528,.F.);
#746=ORIENTED_EDGE('',*,*,#496,.F.);
#747=ORIENTED_EDGE('',*,*,#464,.F.);
#748=ORIENTED_EDGE('',*,*,#432,.F.);
#749=ORIENTED_EDGE('',*,*,#401,.F.);
#750=ORIENTED_EDGE('',*,*,#370,.F.);
#751=ORIENTED_EDGE('',*,*,#338,.F.);
#752=ORIENTED_EDGE('',*,*,#306,.F.);
#753=ORIENTED_EDGE('',*,*,#274,.F.);
#754=ORIENTED_EDGE('',*,*,#242,.F.);
#755=ORIENTED_EDGE('',*,*,#210,.F.);
#756=ORIENTED_EDGE('',*,*,#178,.F.);
#757=ORIENTED_EDGE('',*,*,#139,.F.);
#758=CARTESIAN_POINT('',(17.9451,-2.69240000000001,-12.7));
#759=DIRECTION('',(0.,0.,-1.));
#760=DIRECTION('',(1.,0.,0.));
#761=AXIS2_PLACEMENT_3D('',#758,#759,#760);
#762=CIRCLE('',#761,2.6924);
#763=CARTESIAN_POINT('',(20.6375,-2.69240000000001,-12.7));
#764=VERTEX_POINT('',#763);
#765=EDGE_CURVE('E288',#136,#764,#762,.T.);
#766=ORIENTED_EDGE('',*,*,#765,.T.);
#767=DIRECTION('',(0.,-1.,0.));
#768=VECTOR('',#767,1.);
#769=CARTESIAN_POINT('',(20.6375,-2.69240000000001,-12.7));
#770=LINE('',#769,#768);
#771=CARTESIAN_POINT('',(20.6375,-17.4625,-12.7));
#772=VERTEX_POINT('',#771);
#773=EDGE_CURVE('E293',#764,#772,#770,.T.);
#774=ORIENTED_EDGE('',*,*,#773,.T.);
#775=CARTESIAN_POINT('',(15.875,-17.4625,-12.7));
#776=DIRECTION('',(0.,0.,-1.));
#777=DIRECTION('',(1.,0.,0.));
#778=AXIS2_PLACEMENT_3D('',#775,#776,#777);
#779=CIRCLE('',#778,4.7625);
#780=CARTESIAN_POINT('',(11.1125,-17.4625,-12.7));
#781=VERTEX_POINT('',#780);
#782=EDGE_CURVE('E815',#772,#781,#779,.T.);
#783=ORIENTED_EDGE('',*,*,#782,.T.);
#784=DIRECTION('',(0.,1.,0.));
#785=VECTOR('',#784,1.);
#786=CARTESIAN_POINT('',(11.1125,-17.4625,-12.7));
#787=LINE('',#786,#785);
#788=CARTESIAN_POINT('',(11.1125,-16.42745,-12.7));
#789=VERTEX_POINT('',#788);
#790=EDGE_CURVE('E812',#781,#789,#787,.T.);
#791=ORIENTED_EDGE('',*,*,#790,.T.);
#792=CARTESIAN_POINT('',(12.4587,-16.42745,-12.7));
#793=DIRECTION('',(0.,0.,-1.));
#794=DIRECTION('',(1.,0.,0.));
#795=AXIS2_PLACEMENT_3D('',#792,#793,#794);
#796=CIRCLE('',#795,1.3462);
#797=CARTESIAN_POINT('',(13.8049,-16.42745,-12.7));
#798=VERTEX_POINT('',#797);
#799=EDGE_CURVE('E809',#789,#798,#796,.T.);
#800=ORIENTED_EDGE('',*,*,#799,.T.);
#801=DIRECTION('',(0.,-1.,0.));
#802=VECTOR('',#801,1.);
#803=CARTESIAN_POINT('',(13.8049,-17.4625,-12.7));
#804=LINE('',#803,#802);
#805=CARTESIAN_POINT('',(13.8049,-17.4625,-12.7));
#806=VERTEX_POINT('',#805);
#807=EDGE_CURVE('E806',#798,#806,#804,.T.);
#808=ORIENTED_EDGE('',*,*,#807,.T.);
#809=CARTESIAN_POINT('',(15.875,-17.4625,-12.7));
#810=DIRECTION('',(0.,0.,1.));
#811=DIRECTION('',(1.,0.,0.));
#812=AXIS2_PLACEMENT_3D('',#809,#810,#811);
#813=CIRCLE('',#812,2.07010000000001);
#814=CARTESIAN_POINT('',(17.9451,-17.4625,-12.7));
#815=VERTEX_POINT('',#814);
#816=EDGE_CURVE('E803',#806,#815,#813,.T.);
#817=ORIENTED_EDGE('',*,*,#816,.T.);
#818=DIRECTION('',(0.,1.,0.));
#819=VECTOR('',#818,1.);
#820=CARTESIAN_POINT('',(17.9451,-2.6924,-12.7));
#821=LINE('',#820,#819);
#822=CARTESIAN_POINT('',(17.9451,-2.6924,-12.7));
#823=VERTEX_POINT('',#822);
#824=EDGE_CURVE('E800',#815,#823,#821,.T.);
#825=ORIENTED_EDGE('',*,*,#824,.T.);
#826=DIRECTION('',(-1.,0.,0.));
#827=VECTOR('',#826,1.);
#828=CARTESIAN_POINT('',(-17.9451,-2.6924,-12.7));
#829=LINE('',#828,#827);
#830=CARTESIAN_POINT('',(-17.9451,-2.6924,-12.7));
#831=VERTEX_POINT('',#830);
#832=EDGE_CURVE('E797',#823,#831,#829,.T.);
#833=ORIENTED_EDGE('',*,*,#832,.T.);
#834=DIRECTION('',(0.,-1.,0.));
#835=VECTOR('',#834,1.);
#836=CARTESIAN_POINT('',(-17.9451,-17.4625,-12.7));
#837=LINE('',#836,#835);
#838=CARTESIAN_POINT('',(-17.9451,-17.4625,-12.7));
#839=VERTEX_POINT('',#838);
#840=EDGE_CURVE('E794',#831,#839,#837,.T.);
#841=ORIENTED_EDGE('',*,*,#840,.T.);
#842=CARTESIAN_POINT('',(-15.875,-17.4625,-12.7));
#843=DIRECTION('',(0.,0.,1.));
#844=DIRECTION('',(-1.,0.,0.));
#845=AXIS2_PLACEMENT_3D('',#842,#843,#844);
#846=CIRCLE('',#845,2.0701);
#847=CARTESIAN_POINT('',(-13.8049,-17.4625,-12.7));
#848=VERTEX_POINT('',#847);
#849=EDGE_CURVE('E791',#839,#848,#846,.T.);
#850=ORIENTED_EDGE('',*,*,#849,.T.);
#851=DIRECTION('',(0.,1.,0.));
#852=VECTOR('',#851,1.);
#853=CARTESIAN_POINT('',(-13.8049,-17.4625,-12.7));
#854=LINE('',#853,#852);
#855=CARTESIAN_POINT('',(-13.8049,-16.42745,-12.7));
#856=VERTEX_POINT('',#855);
#857=EDGE_CURVE('E788',#848,#856,#854,.T.);
#858=ORIENTED_EDGE('',*,*,#857,.T.);
#859=CARTESIAN_POINT('',(-12.4587,-16.42745,-12.7));
#860=DIRECTION('',(0.,0.,-1.));
#861=DIRECTION('',(-1.,0.,0.));
#862=AXIS2_PLACEMENT_3D('',#859,#860,#861);
#863=CIRCLE('',#862,1.3462);
#864=CARTESIAN_POINT('',(-11.1125,-16.42745,-12.7));
#865=VERTEX_POINT('',#864);
#866=EDGE_CURVE('E786',#856,#865,#863,.T.);
#867=ORIENTED_EDGE('',*,*,#866,.T.);
#868=DIRECTION('',(0.,-1.,0.));
#869=VECTOR('',#868,1.);
#870=CARTESIAN_POINT('',(-11.1125,-17.4625,-12.7));
#871=LINE('',#870,#869);
#872=CARTESIAN_POINT('',(-11.1125,-17.4625,-12.7));
#873=VERTEX_POINT('',#872);
#874=EDGE_CURVE('E730',#865,#873,#871,.T.);
#875=ORIENTED_EDGE('',*,*,#874,.T.);
#876=CARTESIAN_POINT('',(-15.875,-17.4625,-12.7));
#877=DIRECTION('',(0.,0.,-1.));
#878=DIRECTION('',(-1.,0.,0.));
#879=AXIS2_PLACEMENT_3D('',#876,#877,#878);
#880=CIRCLE('',#879,4.7625);
#881=CARTESIAN_POINT('',(-20.6375,-17.4625,-12.7));
#882=VERTEX_POINT('',#881);
#883=EDGE_CURVE('E783',#873,#882,#880,.T.);
#884=ORIENTED_EDGE('',*,*,#883,.T.);
#885=DIRECTION('',(0.,1.,0.));
#886=VECTOR('',#885,1.);
#887=CARTESIAN_POINT('',(-20.6375,-17.4625,-12.7));
#888=LINE('',#887,#886);
#889=CARTESIAN_POINT('',(-20.6375,-2.6924,-12.7));
#890=VERTEX_POINT('',#889);
#891=EDGE_CURVE('E285',#882,#890,#888,.T.);
#892=ORIENTED_EDGE('',*,*,#891,.T.);
#893=CARTESIAN_POINT('',(-17.9451,-2.6924,-12.7));
#894=DIRECTION('',(0.,0.,-1.));
#895=DIRECTION('',(-1.,0.,0.));
#896=AXIS2_PLACEMENT_3D('',#893,#894,#895);
#897=CIRCLE('',#896,2.6924);
#898=EDGE_CURVE('E281',#890,#103,#897,.T.);
#899=ORIENTED_EDGE('',*,*,#898,.T.);
#900=ORIENTED_EDGE('',*,*,#104,.F.);
#901=ORIENTED_EDGE('',*,*,#72,.F.);
#902=EDGE_LOOP('',(#743,#744,#745,#746,#747,#748,#749,#750,#751,#752,#753,#754,#755,#756,#757,
#766,#774,#783,#791,#800,#808,#817,#825,#833,#841,#850,#858,#867,#875,#884,#892,#899,#900,#901));
#903=FACE_BOUND('',#902,.T.);
#904=ADVANCED_FACE('F278',(#903),#742,.T.);
#905=CARTESIAN_POINT('',(-15.875,-17.4625,12.7));
#906=DIRECTION('',(0.,0.,-1.));
#907=DIRECTION('',(-1.,0.,0.));
#908=AXIS2_PLACEMENT_3D('',#905,#906,#907);
#909=CYLINDRICAL_SURFACE('',#908,4.7625);
#910=ORIENTED_EDGE('',*,*,#883,.F.);
#911=DIRECTION('',(0.,0.,-1.));
#912=VECTOR('',#911,1.);
#913=CARTESIAN_POINT('',(-11.1125,-17.4625,12.7));
#914=LINE('',#913,#912);
#915=EDGE_CURVE('E200',#602,#873,#914,.T.);
#916=ORIENTED_EDGE('',*,*,#915,.F.);
#917=ORIENTED_EDGE('',*,*,#603,.T.);
#918=DIRECTION('',(0.,0.,-1.));
#919=VECTOR('',#918,1.);
#920=CARTESIAN_POINT('',(-20.6375,-17.4625,12.7));
#921=LINE('',#920,#919);
#922=EDGE_CURVE('E297',#593,#882,#921,.T.);
#923=ORIENTED_EDGE('',*,*,#922,.T.);
#924=EDGE_LOOP('',(#910,#916,#917,#923));
#925=FACE_BOUND('',#924,.T.);
#926=ADVANCED_FACE('F472',(#925),#909,.T.);
#927=CARTESIAN_POINT('',(-11.1125,-17.4625,12.7));
#928=DIRECTION('',(1.,0.,0.));
#929=DIRECTION('',(0.,0.,-1.));
#930=AXIS2_PLACEMENT_3D('',#927,#928,#929);
#931=PLANE('',#930);
#932=ORIENTED_EDGE('',*,*,#874,.F.);
#933=DIRECTION('',(0.,0.,-1.));
#934=VECTOR('',#933,1.);
#935=CARTESIAN_POINT('',(-11.1125,-16.42745,12.7));
#936=LINE('',#935,#934);
#937=EDGE_CURVE('E340',#610,#865,#936,.T.);
#938=ORIENTED_EDGE('',*,*,#937,.F.);
#939=ORIENTED_EDGE('',*,*,#611,.T.);
#940=ORIENTED_EDGE('',*,*,#915,.T.);
#941=EDGE_LOOP('',(#932,#938,#939,#940));
#942=FACE_BOUND('',#941,.T.);
#943=ADVANCED_FACE('F483',(#942),#931,.T.);
#944=CARTESIAN_POINT('',(-12.4587,-16.42745,12.7));
#945=DIRECTION('',(0.,0.,-1.));
#946=DIRECTION('',(-1.,0.,0.));
#947=AXIS2_PLACEMENT_3D('',#944,#945,#946);
#948=CYLINDRICAL_SURFACE('',#947,1.3462);
#949=ORIENTED_EDGE('',*,*,#866,.F.);
#950=DIRECTION('',(0.,0.,-1.));
#951=VECTOR('',#950,1.);
#952=CARTESIAN_POINT('',(-13.8049,-16.42745,12.7));
#953=LINE('',#952,#951);
#954=EDGE_CURVE('E337',#619,#856,#953,.T.);
#955=ORIENTED_EDGE('',*,*,#954,.F.);
#956=ORIENTED_EDGE('',*,*,#620,.T.);
#957=ORIENTED_EDGE('',*,*,#937,.T.);
#958=EDGE_LOOP('',(#949,#955,#956,#957));
#959=FACE_BOUND('',#958,.T.);
#960=ADVANCED_FACE('F493',(#959),#948,.T.);
#961=CARTESIAN_POINT('',(-13.8049,-17.4625,12.7));
#962=DIRECTION('',(-1.,0.,0.));
#963=DIRECTION('',(0.,-1.,0.));
#964=AXIS2_PLACEMENT_3D('',#961,#962,#963);
#965=PLANE('',#964);
#966=ORIENTED_EDGE('',*,*,#857,.F.);
#967=DIRECTION('',(0.,0.,-1.));
#968=VECTOR('',#967,1.);
#969=CARTESIAN_POINT('',(-13.8049,-17.4625,12.7));
#970=LINE('',#969,#968);
#971=EDGE_CURVE('E334',#627,#848,#970,.T.);
#972=ORIENTED_EDGE('',*,*,#971,.F.);
#973=ORIENTED_EDGE('',*,*,#628,.T.);
#974=ORIENTED_EDGE('',*,*,#954,.T.);
#975=EDGE_LOOP('',(#966,#972,#973,#974));
#976=FACE_BOUND('',#975,.T.);
#977=ADVANCED_FACE('F503',(#976),#965,.T.);
#978=CARTESIAN_POINT('',(-15.875,-17.4625,12.7));
#979=DIRECTION('',(0.,0.,-1.));
#980=DIRECTION('',(-1.,0.,0.));
#981=AXIS2_PLACEMENT_3D('',#978,#979,#980);
#982=CYLINDRICAL_SURFACE('',#981,2.0701);
#983=ORIENTED_EDGE('',*,*,#849,.F.);
#984=DIRECTION('',(0.,0.,-1.));
#985=VECTOR('',#984,1.);
#986=CARTESIAN_POINT('',(-17.9451,-17.4625,12.7));
#987=LINE('',#986,#985);
#988=EDGE_CURVE('E331',#636,#839,#987,.T.);
#989=ORIENTED_EDGE('',*,*,#988,.F.);
#990=ORIENTED_EDGE('',*,*,#637,.T.);
#991=ORIENTED_EDGE('',*,*,#971,.T.);
#992=EDGE_LOOP('',(#983,#989,#990,#991));
#993=FACE_BOUND('',#992,.T.);
#994=ADVANCED_FACE('F513',(#993),#982,.F.);
#995=CARTESIAN_POINT('',(-17.9451,-17.4625,12.7));
#996=DIRECTION('',(1.,0.,0.));
#997=DIRECTION('',(0.,1.,0.));
#998=AXIS2_PLACEMENT_3D('',#995,#996,#997);
#999=PLANE('',#998);
#1000=ORIENTED_EDGE('',*,*,#840,.F.);
#1001=DIRECTION('',(0.,0.,-1.));
#1002=VECTOR('',#1001,1.);
#1003=CARTESIAN_POINT('',(-17.9451,-2.6924,12.7));
#1004=LINE('',#1003,#1002);
#1005=EDGE_CURVE('E328',#644,#831,#1004,.T.);
#1006=ORIENTED_EDGE('',*,*,#1005,.F.);
#1007=ORIENTED_EDGE('',*,*,#645,.T.);
#1008=ORIENTED_EDGE('',*,*,#988,.T.);
#1009=EDGE_LOOP('',(#1000,#1006,#1007,#1008));
#1010=FACE_BOUND('',#1009,.T.);
#1011=ADVANCED_FACE('F523',(#1010),#999,.T.);
#1012=CARTESIAN_POINT('',(-17.9451,-2.6924,12.7));
#1013=DIRECTION('',(0.,-1.,0.));
#1014=DIRECTION('',(0.,0.,-1.));
#1015=AXIS2_PLACEMENT_3D('',#1012,#1013,#1014);
#1016=PLANE('',#1015);
#1017=ORIENTED_EDGE('',*,*,#832,.F.);
#1018=DIRECTION('',(0.,0.,-1.));
#1019=VECTOR('',#1018,1.);
#1020=CARTESIAN_POINT('',(17.9451,-2.6924,12.7));
#1021=LINE('',#1020,#1019);
#1022=EDGE_CURVE('E325',#652,#823,#1021,.T.);
#1023=ORIENTED_EDGE('',*,*,#1022,.F.);
#1024=ORIENTED_EDGE('',*,*,#653,.T.);
#1025=ORIENTED_EDGE('',*,*,#1005,.T.);
#1026=EDGE_LOOP('',(#1017,#1023,#1024,#1025));
#1027=FACE_BOUND('',#1026,.T.);
#1028=ADVANCED_FACE('F533',(#1027),#1016,.T.);
#1029=CARTESIAN_POINT('',(17.9451,-2.6924,12.7));
#1030=DIRECTION('',(-1.,0.,0.));
#1031=DIRECTION('',(0.,0.,1.));
#1032=AXIS2_PLACEMENT_3D('',#1029,#1030,#1031);
#1033=PLANE('',#1032);
#1034=ORIENTED_EDGE('',*,*,#824,.F.);
#1035=DIRECTION('',(0.,0.,-1.));
#1036=VECTOR('',#1035,1.);
#1037=CARTESIAN_POINT('',(17.9451,-17.4625,12.7));
#1038=LINE('',#1037,#1036);
#1039=EDGE_CURVE('E322',#660,#815,#1038,.T.);
#1040=ORIENTED_EDGE('',*,*,#1039,.F.);
#1041=ORIENTED_EDGE('',*,*,#661,.T.);
#1042=ORIENTED_EDGE('',*,*,#1022,.T.);
#1043=EDGE_LOOP('',(#1034,#1040,#1041,#1042));
#1044=FACE_BOUND('',#1043,.T.);
#1045=ADVANCED_FACE('F543',(#1044),#1033,.T.);
#1046=CARTESIAN_POINT('',(15.875,-17.4625,12.7));
#1047=DIRECTION('',(0.,0.,-1.));
#1048=DIRECTION('',(-1.,0.,0.));
#1049=AXIS2_PLACEMENT_3D('',#1046,#1047,#1048);
#1050=CYLINDRICAL_SURFACE('',#1049,2.07010000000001);
#1051=ORIENTED_EDGE('',*,*,#816,.F.);
#1052=DIRECTION('',(0.,0.,-1.));
#1053=VECTOR('',#1052,1.);
#1054=CARTESIAN_POINT('',(13.8049,-17.4625,12.7));
#1055=LINE('',#1054,#1053);
#1056=EDGE_CURVE('E319',#669,#806,#1055,.T.);
#1057=ORIENTED_EDGE('',*,*,#1056,.F.);
#1058=ORIENTED_EDGE('',*,*,#670,.T.);
#1059=ORIENTED_EDGE('',*,*,#1039,.T.);
#1060=EDGE_LOOP('',(#1051,#1057,#1058,#1059));
#1061=FACE_BOUND('',#1060,.T.);
#1062=ADVANCED_FACE('F553',(#1061),#1050,.F.);
#1063=CARTESIAN_POINT('',(13.8049,-17.4625,12.7));
#1064=DIRECTION('',(1.,0.,0.));
#1065=DIRECTION('',(0.,1.,0.));
#1066=AXIS2_PLACEMENT_3D('',#1063,#1064,#1065);
#1067=PLANE('',#1066);
#1068=ORIENTED_EDGE('',*,*,#807,.F.);
#1069=DIRECTION('',(0.,0.,-1.));
#1070=VECTOR('',#1069,1.);
#1071=CARTESIAN_POINT('',(13.8049,-16.42745,12.7));
#1072=LINE('',#1071,#1070);
#1073=EDGE_CURVE('E316',#677,#798,#1072,.T.);
#1074=ORIENTED_EDGE('',*,*,#1073,.F.);
#1075=ORIENTED_EDGE('',*,*,#678,.T.);
#1076=ORIENTED_EDGE('',*,*,#1056,.T.);
#1077=EDGE_LOOP('',(#1068,#1074,#1075,#1076));
#1078=FACE_BOUND('',#1077,.T.);
#1079=ADVANCED_FACE('F563',(#1078),#1067,.T.);
#1080=CARTESIAN_POINT('',(12.4587,-16.42745,12.7));
#1081=DIRECTION('',(0.,0.,-1.));
#1082=DIRECTION('',(-1.,0.,0.));
#1083=AXIS2_PLACEMENT_3D('',#1080,#1081,#1082);
#1084=CYLINDRICAL_SURFACE('',#1083,1.3462);
#1085=ORIENTED_EDGE('',*,*,#799,.F.);
#1086=DIRECTION('',(0.,0.,-1.));
#1087=VECTOR('',#1086,1.);
#1088=CARTESIAN_POINT('',(11.1125,-16.42745,12.7));
#1089=LINE('',#1088,#1087);
#1090=EDGE_CURVE('E313',#686,#789,#1089,.T.);
#1091=ORIENTED_EDGE('',*,*,#1090,.F.);
#1092=ORIENTED_EDGE('',*,*,#687,.T.);
#1093=ORIENTED_EDGE('',*,*,#1073,.T.);
#1094=EDGE_LOOP('',(#1085,#1091,#1092,#1093));
#1095=FACE_BOUND('',#1094,.T.);
#1096=ADVANCED_FACE('F573',(#1095),#1084,.T.);
#1097=CARTESIAN_POINT('',(11.1125,-17.4625,12.7));
#1098=DIRECTION('',(-1.,0.,0.));
#1099=DIRECTION('',(0.,0.,1.));
#1100=AXIS2_PLACEMENT_3D('',#1097,#1098,#1099);
#1101=PLANE('',#1100);
#1102=ORIENTED_EDGE('',*,*,#790,.F.);
#1103=DIRECTION('',(0.,0.,-1.));
#1104=VECTOR('',#1103,1.);
#1105=CARTESIAN_POINT('',(11.1125,-17.4625,12.7));
#1106=LINE('',#1105,#1104);
#1107=EDGE_CURVE('E310',#694,#781,#1106,.T.);
#1108=ORIENTED_EDGE('',*,*,#1107,.F.);
#1109=ORIENTED_EDGE('',*,*,#695,.T.);
#1110=ORIENTED_EDGE('',*,*,#1090,.T.);
#1111=EDGE_LOOP('',(#1102,#1108,#1109,#1110));
#1112=FACE_BOUND('',#1111,.T.);
#1113=ADVANCED_FACE('F583',(#1112),#1101,.T.);
#1114=CARTESIAN_POINT('',(15.875,-17.4625,12.7));
#1115=DIRECTION('',(0.,0.,-1.));
#1116=DIRECTION('',(-1.,0.,0.));
#1117=AXIS2_PLACEMENT_3D('',#1114,#1115,#1116);
#1118=CYLINDRICAL_SURFACE('',#1117,4.7625);
#1119=ORIENTED_EDGE('',*,*,#782,.F.);
#1120=DIRECTION('',(0.,0.,-1.));
#1121=VECTOR('',#1120,1.);
#1122=CARTESIAN_POINT('',(20.6375,-17.4625,12.7));
#1123=LINE('',#1122,#1121);
#1124=EDGE_CURVE('E307',#703,#772,#1123,.T.);
#1125=ORIENTED_EDGE('',*,*,#1124,.F.);
#1126=ORIENTED_EDGE('',*,*,#704,.T.);
#1127=ORIENTED_EDGE('',*,*,#1107,.T.);
#1128=EDGE_LOOP('',(#1119,#1125,#1126,#1127));
#1129=FACE_BOUND('',#1128,.T.);
#1130=ADVANCED_FACE('F593',(#1129),#1118,.T.);
#1131=CARTESIAN_POINT('',(20.6375,-2.69240000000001,12.7));
#1132=DIRECTION('',(1.,0.,0.));
#1133=DIRECTION('',(0.,1.,0.));
#1134=AXIS2_PLACEMENT_3D('',#1131,#1132,#1133);
#1135=PLANE('',#1134);
#1136=ORIENTED_EDGE('',*,*,#773,.F.);
#1137=DIRECTION('',(0.,0.,-1.));
#1138=VECTOR('',#1137,1.);
#1139=CARTESIAN_POINT('',(20.6375,-2.69240000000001,12.7));
#1140=LINE('',#1139,#1138);
#1141=EDGE_CURVE('E304',#711,#764,#1140,.T.);
#1142=ORIENTED_EDGE('',*,*,#1141,.F.);
#1143=ORIENTED_EDGE('',*,*,#712,.T.);
#1144=ORIENTED_EDGE('',*,*,#1124,.T.);
#1145=EDGE_LOOP('',(#1136,#1142,#1143,#1144));
#1146=FACE_BOUND('',#1145,.T.);
#1147=ADVANCED_FACE('F603',(#1146),#1135,.T.);
#1148=CARTESIAN_POINT('',(17.9451,-2.69240000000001,12.7));
#1149=DIRECTION('',(0.,0.,-1.));
#1150=DIRECTION('',(-1.,0.,0.));
#1151=AXIS2_PLACEMENT_3D('',#1148,#1149,#1150);
#1152=CYLINDRICAL_SURFACE('',#1151,2.6924);
#1153=ORIENTED_EDGE('',*,*,#765,.F.);
#1154=ORIENTED_EDGE('',*,*,#162,.F.);
#1155=ORIENTED_EDGE('',*,*,#719,.T.);
#1156=ORIENTED_EDGE('',*,*,#1141,.T.);
#1157=EDGE_LOOP('',(#1153,#1154,#1155,#1156));
#1158=FACE_BOUND('',#1157,.T.);
#1159=ADVANCED_FACE('F613',(#1158),#1152,.T.);
#1160=CARTESIAN_POINT('',(-17.9451,-2.6924,12.7));
#1161=DIRECTION('',(0.,0.,-1.));
#1162=DIRECTION('',(-1.,0.,0.));
#1163=AXIS2_PLACEMENT_3D('',#1160,#1161,#1162);
#1164=CYLINDRICAL_SURFACE('',#1163,2.6924);
#1165=ORIENTED_EDGE('',*,*,#898,.F.);
#1166=DIRECTION('',(0.,0.,-1.));
#1167=VECTOR('',#1166,1.);
#1168=CARTESIAN_POINT('',(-20.6375,-2.6924,12.7));
#1169=LINE('',#1168,#1167);
#1170=EDGE_CURVE('E300',#585,#890,#1169,.T.);
#1171=ORIENTED_EDGE('',*,*,#1170,.F.);
#1172=ORIENTED_EDGE('',*,*,#586,.T.);
#1173=ORIENTED_EDGE('',*,*,#112,.T.);
#1174=EDGE_LOOP('',(#1165,#1171,#1172,#1173));
#1175=FACE_BOUND('',#1174,.T.);
#1176=ADVANCED_FACE('F623',(#1175),#1164,.T.);
#1177=CARTESIAN_POINT('',(-20.6375,-17.4625,12.7));
#1178=DIRECTION('',(-1.,0.,0.));
#1179=DIRECTION('',(0.,-1.,0.));
#1180=AXIS2_PLACEMENT_3D('',#1177,#1178,#1179);
#1181=PLANE('',#1180);
#1182=ORIENTED_EDGE('',*,*,#891,.F.);
#1183=ORIENTED_EDGE('',*,*,#922,.F.);
#1184=ORIENTED_EDGE('',*,*,#594,.T.);
#1185=ORIENTED_EDGE('',*,*,#1170,.T.);
#1186=EDGE_LOOP('',(#1182,#1183,#1184,#1185));
#1187=FACE_BOUND('',#1186,.T.);
#1188=ADVANCED_FACE('F633',(#1187),#1181,.T.);
#1189=CLOSED_SHELL('',(#60,#91,#124,#166,#197,#230,#261,#294,#325,#358,#389,#420,#451,#484,#515,
#548,#570,#737,#904,#926,#943,#960,#977,#994,#1011,#1028,#1045,#1062,#1079,#1096,#1113,#1130,
#1147,#1159,#1176,#1188));
#1190=MANIFOLD_SOLID_BREP('B2',#1189);
#1191=ADVANCED_BREP_SHAPE_REPRESENTATION('',(#18,#1190),#14);
#1192=SHAPE_DEFINITION_REPRESENTATION(#9,#1191);
ENDSEC;
END-ISO-10303-21;
